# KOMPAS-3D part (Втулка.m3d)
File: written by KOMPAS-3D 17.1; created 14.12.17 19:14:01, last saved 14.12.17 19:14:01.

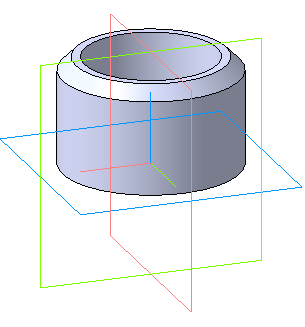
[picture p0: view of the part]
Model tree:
1. Операция без истории:1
